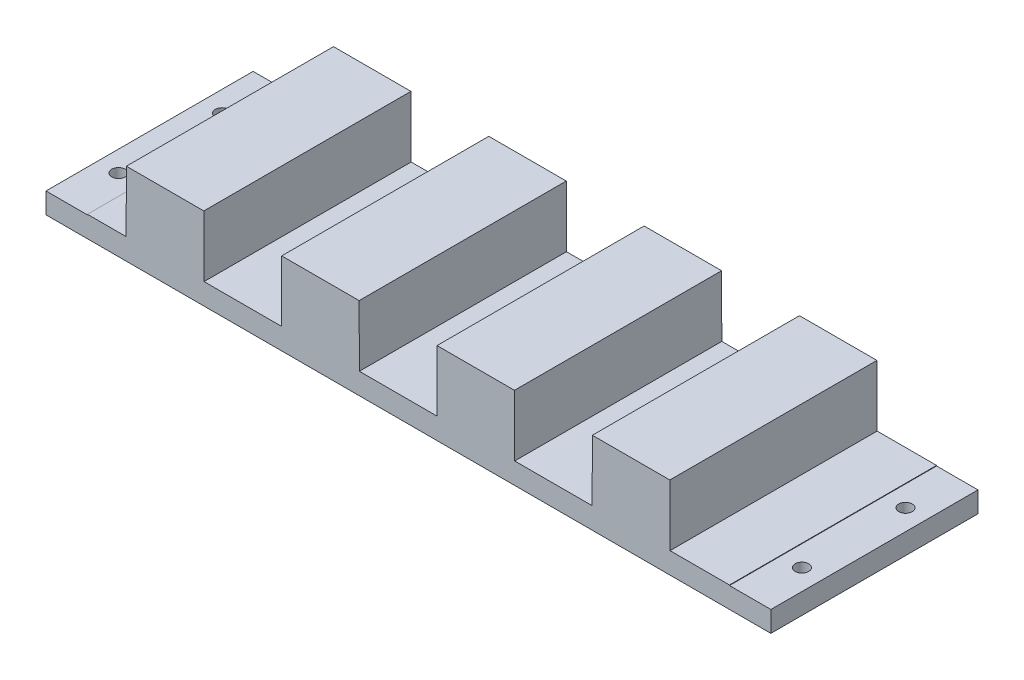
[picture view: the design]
ISO-10303-21;
HEADER;
FILE_DESCRIPTION(('STEP AP214'),'2;1');
FILE_NAME('part.step','',(''),(''),'','','');
FILE_SCHEMA(('AUTOMOTIVE_DESIGN { 1 0 10303 214 1 1 1 1 }'));
ENDSEC;
DATA;
#1=APPLICATION_CONTEXT('core data for automotive mechanical design processes');
#2=APPLICATION_PROTOCOL_DEFINITION('international standard','automotive_design',2000,#1);
#3=PRODUCT_CONTEXT('',#1,'mechanical');
#4=PRODUCT('Part','Part','',(#3));
#5=PRODUCT_RELATED_PRODUCT_CATEGORY('part','',(#4));
#6=PRODUCT_DEFINITION_FORMATION('','',#4);
#7=PRODUCT_DEFINITION_CONTEXT('part definition',#1,'design');
#8=PRODUCT_DEFINITION('design','',#6,#7);
#9=PRODUCT_DEFINITION_SHAPE('','',#8);
#10=(LENGTH_UNIT() NAMED_UNIT(*) SI_UNIT(.MILLI.,.METRE.));
#11=(NAMED_UNIT(*) PLANE_ANGLE_UNIT() SI_UNIT($,.RADIAN.));
#12=(NAMED_UNIT(*) SI_UNIT($,.STERADIAN.) SOLID_ANGLE_UNIT());
#13=UNCERTAINTY_MEASURE_WITH_UNIT(LENGTH_MEASURE(1.E-05),#10,'distance_accuracy_value','');
#14=(GEOMETRIC_REPRESENTATION_CONTEXT(3) GLOBAL_UNCERTAINTY_ASSIGNED_CONTEXT((#13)) GLOBAL_UNIT_ASSIGNED_CONTEXT((#10,
#11,#12)) REPRESENTATION_CONTEXT('',''));
#15=CARTESIAN_POINT('',(0.,0.,0.));
#16=DIRECTION('',(0.,0.,1.));
#17=DIRECTION('',(1.,0.,0.));
#18=AXIS2_PLACEMENT_3D('',#15,#16,#17);
#19=CARTESIAN_POINT('',(0.,0.246057,100.));
#20=DIRECTION('',(1.,0.,0.));
#21=DIRECTION('',(0.,0.,-1.));
#22=AXIS2_PLACEMENT_3D('',#19,#20,#21);
#23=PLANE('',#22);
#24=DIRECTION('',(0.,-1.,0.));
#25=VECTOR('',#24,1.);
#26=CARTESIAN_POINT('',(0.,0.246057,0.));
#27=LINE('',#26,#25);
#28=CARTESIAN_POINT('',(0.,0.246057,0.));
#29=VERTEX_POINT('',#28);
#30=CARTESIAN_POINT('',(0.,0.,0.));
#31=VERTEX_POINT('',#30);
#32=EDGE_CURVE('E229',#29,#31,#27,.T.);
#33=ORIENTED_EDGE('',*,*,#32,.T.);
#34=DIRECTION('',(0.,0.,-1.));
#35=VECTOR('',#34,1.);
#36=CARTESIAN_POINT('',(0.,0.,100.));
#37=LINE('',#36,#35);
#38=CARTESIAN_POINT('',(0.,0.,100.));
#39=VERTEX_POINT('',#38);
#40=EDGE_CURVE('E11',#39,#31,#37,.T.);
#41=ORIENTED_EDGE('',*,*,#40,.F.);
#42=DIRECTION('',(0.,-1.,0.));
#43=VECTOR('',#42,1.);
#44=CARTESIAN_POINT('',(0.,0.246057,100.));
#45=LINE('',#44,#43);
#46=CARTESIAN_POINT('',(0.,0.246057,100.));
#47=VERTEX_POINT('',#46);
#48=EDGE_CURVE('E285',#47,#39,#45,.T.);
#49=ORIENTED_EDGE('',*,*,#48,.F.);
#50=DIRECTION('',(0.,0.,-1.));
#51=VECTOR('',#50,1.);
#52=CARTESIAN_POINT('',(0.,0.246057,100.));
#53=LINE('',#52,#51);
#54=EDGE_CURVE('E225',#47,#29,#53,.T.);
#55=ORIENTED_EDGE('',*,*,#54,.T.);
#56=EDGE_LOOP('',(#33,#41,#49,#55));
#57=FACE_BOUND('',#56,.T.);
#58=ADVANCED_FACE('F35',(#57),#23,.F.);
#59=CARTESIAN_POINT('',(0.,0.,100.));
#60=DIRECTION('',(0.,-1.,0.));
#61=DIRECTION('',(1.,0.,0.));
#62=AXIS2_PLACEMENT_3D('',#59,#60,#61);
#63=PLANE('',#62);
#64=CARTESIAN_POINT('',(-10.,0.,25.));
#65=DIRECTION('',(0.,-1.,0.));
#66=DIRECTION('',(1.,0.,0.));
#67=AXIS2_PLACEMENT_3D('',#64,#65,#66);
#68=CIRCLE('',#67,3.25);
#69=CARTESIAN_POINT('',(-6.75,0.,25.));
#70=VERTEX_POINT('',#69);
#71=EDGE_CURVE('E233',#70,#70,#68,.T.);
#72=ORIENTED_EDGE('',*,*,#71,.T.);
#73=EDGE_LOOP('',(#72));
#74=FACE_BOUND('',#73,.T.);
#75=CARTESIAN_POINT('',(-10.,0.,75.));
#76=DIRECTION('',(0.,-1.,0.));
#77=DIRECTION('',(1.,0.,0.));
#78=AXIS2_PLACEMENT_3D('',#75,#76,#77);
#79=CIRCLE('',#78,3.25);
#80=CARTESIAN_POINT('',(-6.75,0.,75.));
#81=VERTEX_POINT('',#80);
#82=EDGE_CURVE('E354',#81,#81,#79,.T.);
#83=ORIENTED_EDGE('',*,*,#82,.T.);
#84=EDGE_LOOP('',(#83));
#85=FACE_BOUND('',#84,.T.);
#86=DIRECTION('',(-1.,0.,0.));
#87=VECTOR('',#86,1.);
#88=CARTESIAN_POINT('',(0.,0.,0.));
#89=LINE('',#88,#87);
#90=CARTESIAN_POINT('',(-20.,0.,0.));
#91=VERTEX_POINT('',#90);
#92=EDGE_CURVE('E232',#31,#91,#89,.T.);
#93=ORIENTED_EDGE('',*,*,#92,.T.);
#94=DIRECTION('',(0.,0.,-1.));
#95=VECTOR('',#94,1.);
#96=CARTESIAN_POINT('',(-20.,0.,100.));
#97=LINE('',#96,#95);
#98=CARTESIAN_POINT('',(-20.,0.,100.));
#99=VERTEX_POINT('',#98);
#100=EDGE_CURVE('E44',#99,#91,#97,.T.);
#101=ORIENTED_EDGE('',*,*,#100,.F.);
#102=DIRECTION('',(-1.,0.,0.));
#103=VECTOR('',#102,1.);
#104=CARTESIAN_POINT('',(0.,0.,100.));
#105=LINE('',#104,#103);
#106=EDGE_CURVE('E142',#39,#99,#105,.T.);
#107=ORIENTED_EDGE('',*,*,#106,.F.);
#108=ORIENTED_EDGE('',*,*,#40,.T.);
#109=EDGE_LOOP('',(#93,#101,#107,#108));
#110=FACE_BOUND('',#109,.T.);
#111=ADVANCED_FACE('F421',(#74,#85,#110),#63,.F.);
#112=CARTESIAN_POINT('',(-20.,0.,100.));
#113=DIRECTION('',(1.,0.,0.));
#114=DIRECTION('',(0.,0.,-1.));
#115=AXIS2_PLACEMENT_3D('',#112,#113,#114);
#116=PLANE('',#115);
#117=DIRECTION('',(0.,-1.,0.));
#118=VECTOR('',#117,1.);
#119=CARTESIAN_POINT('',(-20.,0.,0.));
#120=LINE('',#119,#118);
#121=CARTESIAN_POINT('',(-20.,-10.,0.));
#122=VERTEX_POINT('',#121);
#123=EDGE_CURVE('E235',#91,#122,#120,.T.);
#124=ORIENTED_EDGE('',*,*,#123,.T.);
#125=DIRECTION('',(0.,0.,-1.));
#126=VECTOR('',#125,1.);
#127=CARTESIAN_POINT('',(-20.,-10.,100.));
#128=LINE('',#127,#126);
#129=CARTESIAN_POINT('',(-20.,-10.,100.));
#130=VERTEX_POINT('',#129);
#131=EDGE_CURVE('E340',#130,#122,#128,.T.);
#132=ORIENTED_EDGE('',*,*,#131,.F.);
#133=DIRECTION('',(0.,-1.,0.));
#134=VECTOR('',#133,1.);
#135=CARTESIAN_POINT('',(-20.,0.,100.));
#136=LINE('',#135,#134);
#137=EDGE_CURVE('E369',#99,#130,#136,.T.);
#138=ORIENTED_EDGE('',*,*,#137,.F.);
#139=ORIENTED_EDGE('',*,*,#100,.T.);
#140=EDGE_LOOP('',(#124,#132,#138,#139));
#141=FACE_BOUND('',#140,.T.);
#142=ADVANCED_FACE('F424',(#141),#116,.F.);
#143=CARTESIAN_POINT('',(-20.,-10.,100.));
#144=DIRECTION('',(0.,1.,0.));
#145=DIRECTION('',(-1.,0.,0.));
#146=AXIS2_PLACEMENT_3D('',#143,#144,#145);
#147=PLANE('',#146);
#148=CARTESIAN_POINT('',(-10.,-10.,25.));
#149=DIRECTION('',(0.,1.,0.));
#150=DIRECTION('',(-1.,0.,0.));
#151=AXIS2_PLACEMENT_3D('',#148,#149,#150);
#152=CIRCLE('',#151,3.25);
#153=CARTESIAN_POINT('',(-6.75,-9.99999999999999,25.));
#154=VERTEX_POINT('',#153);
#155=EDGE_CURVE('E38',#154,#154,#152,.T.);
#156=ORIENTED_EDGE('',*,*,#155,.T.);
#157=EDGE_LOOP('',(#156));
#158=FACE_BOUND('',#157,.T.);
#159=CARTESIAN_POINT('',(320.,-10.,25.));
#160=DIRECTION('',(0.,1.,0.));
#161=DIRECTION('',(-1.,0.,0.));
#162=AXIS2_PLACEMENT_3D('',#159,#160,#161);
#163=CIRCLE('',#162,3.25000000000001);
#164=CARTESIAN_POINT('',(323.25,-9.99999999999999,25.));
#165=VERTEX_POINT('',#164);
#166=EDGE_CURVE('E351',#165,#165,#163,.T.);
#167=ORIENTED_EDGE('',*,*,#166,.T.);
#168=EDGE_LOOP('',(#167));
#169=FACE_BOUND('',#168,.T.);
#170=CARTESIAN_POINT('',(320.,-10.,75.));
#171=DIRECTION('',(0.,1.,0.));
#172=DIRECTION('',(-1.,0.,0.));
#173=AXIS2_PLACEMENT_3D('',#170,#171,#172);
#174=CIRCLE('',#173,3.25000000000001);
#175=CARTESIAN_POINT('',(323.25,-9.99999999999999,75.));
#176=VERTEX_POINT('',#175);
#177=EDGE_CURVE('E348',#176,#176,#174,.T.);
#178=ORIENTED_EDGE('',*,*,#177,.T.);
#179=EDGE_LOOP('',(#178));
#180=FACE_BOUND('',#179,.T.);
#181=CARTESIAN_POINT('',(-10.,-10.,75.));
#182=DIRECTION('',(0.,1.,0.));
#183=DIRECTION('',(-1.,0.,0.));
#184=AXIS2_PLACEMENT_3D('',#181,#182,#183);
#185=CIRCLE('',#184,3.25);
#186=CARTESIAN_POINT('',(-6.75,-9.99999999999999,75.));
#187=VERTEX_POINT('',#186);
#188=EDGE_CURVE('E352',#187,#187,#185,.T.);
#189=ORIENTED_EDGE('',*,*,#188,.T.);
#190=EDGE_LOOP('',(#189));
#191=FACE_BOUND('',#190,.T.);
#192=DIRECTION('',(1.,0.,0.));
#193=VECTOR('',#192,1.);
#194=CARTESIAN_POINT('',(-20.,-10.,0.));
#195=LINE('',#194,#193);
#196=CARTESIAN_POINT('',(330.,-10.,0.));
#197=VERTEX_POINT('',#196);
#198=EDGE_CURVE('E237',#122,#197,#195,.T.);
#199=ORIENTED_EDGE('',*,*,#198,.T.);
#200=DIRECTION('',(0.,0.,-1.));
#201=VECTOR('',#200,1.);
#202=CARTESIAN_POINT('',(330.,-10.,100.));
#203=LINE('',#202,#201);
#204=CARTESIAN_POINT('',(330.,-10.,100.));
#205=VERTEX_POINT('',#204);
#206=EDGE_CURVE('E337',#205,#197,#203,.T.);
#207=ORIENTED_EDGE('',*,*,#206,.F.);
#208=DIRECTION('',(1.,0.,0.));
#209=VECTOR('',#208,1.);
#210=CARTESIAN_POINT('',(-20.,-10.,100.));
#211=LINE('',#210,#209);
#212=EDGE_CURVE('E371',#130,#205,#211,.T.);
#213=ORIENTED_EDGE('',*,*,#212,.F.);
#214=ORIENTED_EDGE('',*,*,#131,.T.);
#215=EDGE_LOOP('',(#199,#207,#213,#214));
#216=FACE_BOUND('',#215,.T.);
#217=ADVANCED_FACE('F429',(#158,#169,#180,#191,#216),#147,.F.);
#218=CARTESIAN_POINT('',(330.,-10.,100.));
#219=DIRECTION('',(-1.,0.,0.));
#220=DIRECTION('',(0.,0.,1.));
#221=AXIS2_PLACEMENT_3D('',#218,#219,#220);
#222=PLANE('',#221);
#223=DIRECTION('',(0.,1.,0.));
#224=VECTOR('',#223,1.);
#225=CARTESIAN_POINT('',(330.,-10.,0.));
#226=LINE('',#225,#224);
#227=CARTESIAN_POINT('',(330.,0.,0.));
#228=VERTEX_POINT('',#227);
#229=EDGE_CURVE('E239',#197,#228,#226,.T.);
#230=ORIENTED_EDGE('',*,*,#229,.T.);
#231=DIRECTION('',(0.,0.,-1.));
#232=VECTOR('',#231,1.);
#233=CARTESIAN_POINT('',(330.,0.,100.));
#234=LINE('',#233,#232);
#235=CARTESIAN_POINT('',(330.,0.,100.));
#236=VERTEX_POINT('',#235);
#237=EDGE_CURVE('E334',#236,#228,#234,.T.);
#238=ORIENTED_EDGE('',*,*,#237,.F.);
#239=DIRECTION('',(0.,1.,0.));
#240=VECTOR('',#239,1.);
#241=CARTESIAN_POINT('',(330.,-10.,100.));
#242=LINE('',#241,#240);
#243=EDGE_CURVE('E373',#205,#236,#242,.T.);
#244=ORIENTED_EDGE('',*,*,#243,.F.);
#245=ORIENTED_EDGE('',*,*,#206,.T.);
#246=EDGE_LOOP('',(#230,#238,#244,#245));
#247=FACE_BOUND('',#246,.T.);
#248=ADVANCED_FACE('F435',(#247),#222,.F.);
#249=CARTESIAN_POINT('',(330.,0.,100.));
#250=DIRECTION('',(0.,-1.,0.));
#251=DIRECTION('',(1.,0.,0.));
#252=AXIS2_PLACEMENT_3D('',#249,#250,#251);
#253=PLANE('',#252);
#254=CARTESIAN_POINT('',(320.,0.,25.));
#255=DIRECTION('',(0.,-1.,0.));
#256=DIRECTION('',(1.,0.,0.));
#257=AXIS2_PLACEMENT_3D('',#254,#255,#256);
#258=CIRCLE('',#257,3.25000000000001);
#259=CARTESIAN_POINT('',(323.25,0.,25.));
#260=VERTEX_POINT('',#259);
#261=EDGE_CURVE('E349',#260,#260,#258,.T.);
#262=ORIENTED_EDGE('',*,*,#261,.T.);
#263=EDGE_LOOP('',(#262));
#264=FACE_BOUND('',#263,.T.);
#265=CARTESIAN_POINT('',(320.,0.,75.));
#266=DIRECTION('',(0.,-1.,0.));
#267=DIRECTION('',(1.,0.,0.));
#268=AXIS2_PLACEMENT_3D('',#265,#266,#267);
#269=CIRCLE('',#268,3.25000000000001);
#270=CARTESIAN_POINT('',(323.25,0.,75.));
#271=VERTEX_POINT('',#270);
#272=EDGE_CURVE('E345',#271,#271,#269,.T.);
#273=ORIENTED_EDGE('',*,*,#272,.T.);
#274=EDGE_LOOP('',(#273));
#275=FACE_BOUND('',#274,.T.);
#276=DIRECTION('',(-1.,0.,0.));
#277=VECTOR('',#276,1.);
#278=CARTESIAN_POINT('',(330.,0.,0.));
#279=LINE('',#278,#277);
#280=CARTESIAN_POINT('',(310.000009,0.,0.));
#281=VERTEX_POINT('',#280);
#282=EDGE_CURVE('E241',#228,#281,#279,.T.);
#283=ORIENTED_EDGE('',*,*,#282,.T.);
#284=DIRECTION('',(0.,0.,-1.));
#285=VECTOR('',#284,1.);
#286=CARTESIAN_POINT('',(310.000009,0.,100.));
#287=LINE('',#286,#285);
#288=CARTESIAN_POINT('',(310.000009,0.,100.));
#289=VERTEX_POINT('',#288);
#290=EDGE_CURVE('E331',#289,#281,#287,.T.);
#291=ORIENTED_EDGE('',*,*,#290,.F.);
#292=DIRECTION('',(-1.,0.,0.));
#293=VECTOR('',#292,1.);
#294=CARTESIAN_POINT('',(330.,0.,100.));
#295=LINE('',#294,#293);
#296=EDGE_CURVE('E375',#236,#289,#295,.T.);
#297=ORIENTED_EDGE('',*,*,#296,.F.);
#298=ORIENTED_EDGE('',*,*,#237,.T.);
#299=EDGE_LOOP('',(#283,#291,#297,#298));
#300=FACE_BOUND('',#299,.T.);
#301=ADVANCED_FACE('F439',(#264,#275,#300),#253,.F.);
#302=CARTESIAN_POINT('',(310.000009,0.,100.));
#303=DIRECTION('',(-1.,0.,0.));
#304=DIRECTION('',(0.,0.,1.));
#305=AXIS2_PLACEMENT_3D('',#302,#303,#304);
#306=PLANE('',#305);
#307=DIRECTION('',(0.,1.,0.));
#308=VECTOR('',#307,1.);
#309=CARTESIAN_POINT('',(310.000009,0.,0.));
#310=LINE('',#309,#308);
#311=CARTESIAN_POINT('',(310.000009,0.246057,0.));
#312=VERTEX_POINT('',#311);
#313=EDGE_CURVE('E243',#281,#312,#310,.T.);
#314=ORIENTED_EDGE('',*,*,#313,.T.);
#315=DIRECTION('',(0.,0.,-1.));
#316=VECTOR('',#315,1.);
#317=CARTESIAN_POINT('',(310.000009,0.246057,100.));
#318=LINE('',#317,#316);
#319=CARTESIAN_POINT('',(310.000009,0.246057,100.));
#320=VERTEX_POINT('',#319);
#321=EDGE_CURVE('E328',#320,#312,#318,.T.);
#322=ORIENTED_EDGE('',*,*,#321,.F.);
#323=DIRECTION('',(0.,1.,0.));
#324=VECTOR('',#323,1.);
#325=CARTESIAN_POINT('',(310.000009,0.,100.));
#326=LINE('',#325,#324);
#327=EDGE_CURVE('E377',#289,#320,#326,.T.);
#328=ORIENTED_EDGE('',*,*,#327,.F.);
#329=ORIENTED_EDGE('',*,*,#290,.T.);
#330=EDGE_LOOP('',(#314,#322,#328,#329));
#331=FACE_BOUND('',#330,.T.);
#332=ADVANCED_FACE('F444',(#331),#306,.F.);
#333=CARTESIAN_POINT('',(281.300013,0.246057,100.));
#334=DIRECTION('',(0.,-1.,0.));
#335=DIRECTION('',(0.,0.,-1.));
#336=AXIS2_PLACEMENT_3D('',#333,#334,#335);
#337=PLANE('',#336);
#338=DIRECTION('',(-1.,0.,0.));
#339=VECTOR('',#338,1.);
#340=CARTESIAN_POINT('',(281.300013,0.246057,0.));
#341=LINE('',#340,#339);
#342=CARTESIAN_POINT('',(281.300013,0.246057,0.));
#343=VERTEX_POINT('',#342);
#344=EDGE_CURVE('E246',#312,#343,#341,.T.);
#345=ORIENTED_EDGE('',*,*,#344,.T.);
#346=DIRECTION('',(0.,0.,-1.));
#347=VECTOR('',#346,1.);
#348=CARTESIAN_POINT('',(281.300013,0.246057,100.));
#349=LINE('',#348,#347);
#350=CARTESIAN_POINT('',(281.300013,0.246057,100.));
#351=VERTEX_POINT('',#350);
#352=EDGE_CURVE('E325',#351,#343,#349,.T.);
#353=ORIENTED_EDGE('',*,*,#352,.F.);
#354=DIRECTION('',(-1.,0.,0.));
#355=VECTOR('',#354,1.);
#356=CARTESIAN_POINT('',(309.899991,0.246057,100.));
#357=LINE('',#356,#355);
#358=EDGE_CURVE('E379',#320,#351,#357,.T.);
#359=ORIENTED_EDGE('',*,*,#358,.F.);
#360=ORIENTED_EDGE('',*,*,#321,.T.);
#361=EDGE_LOOP('',(#345,#353,#359,#360));
#362=FACE_BOUND('',#361,.T.);
#363=ADVANCED_FACE('F450',(#362),#337,.F.);
#364=CARTESIAN_POINT('',(281.200032,29.749822,100.));
#365=DIRECTION('',(-0.999994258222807,-0.00338873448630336,0.));
#366=DIRECTION('',(0.00338873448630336,-0.999994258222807,0.));
#367=AXIS2_PLACEMENT_3D('',#364,#365,#366);
#368=PLANE('',#367);
#369=DIRECTION('',(-0.00338873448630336,0.999994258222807,0.));
#370=VECTOR('',#369,1.);
#371=CARTESIAN_POINT('',(281.200032,29.749822,0.));
#372=LINE('',#371,#370);
#373=CARTESIAN_POINT('',(281.200032,29.749822,0.));
#374=VERTEX_POINT('',#373);
#375=EDGE_CURVE('E248',#343,#374,#372,.T.);
#376=ORIENTED_EDGE('',*,*,#375,.T.);
#377=DIRECTION('',(0.,0.,-1.));
#378=VECTOR('',#377,1.);
#379=CARTESIAN_POINT('',(281.200032,29.749822,100.));
#380=LINE('',#379,#378);
#381=CARTESIAN_POINT('',(281.200032,29.749822,100.));
#382=VERTEX_POINT('',#381);
#383=EDGE_CURVE('E322',#382,#374,#380,.T.);
#384=ORIENTED_EDGE('',*,*,#383,.F.);
#385=DIRECTION('',(-0.00338873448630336,0.999994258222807,0.));
#386=VECTOR('',#385,1.);
#387=CARTESIAN_POINT('',(281.200032,29.749822,100.));
#388=LINE('',#387,#386);
#389=EDGE_CURVE('E381',#351,#382,#388,.T.);
#390=ORIENTED_EDGE('',*,*,#389,.F.);
#391=ORIENTED_EDGE('',*,*,#352,.T.);
#392=EDGE_LOOP('',(#376,#384,#390,#391));
#393=FACE_BOUND('',#392,.T.);
#394=ADVANCED_FACE('F453',(#393),#368,.F.);
#395=CARTESIAN_POINT('',(243.800032,29.749822,100.));
#396=DIRECTION('',(0.,-1.,0.));
#397=DIRECTION('',(0.,0.,-1.));
#398=AXIS2_PLACEMENT_3D('',#395,#396,#397);
#399=PLANE('',#398);
#400=DIRECTION('',(-1.,0.,0.));
#401=VECTOR('',#400,1.);
#402=CARTESIAN_POINT('',(243.800032,29.749822,0.));
#403=LINE('',#402,#401);
#404=CARTESIAN_POINT('',(243.800032,29.749822,0.));
#405=VERTEX_POINT('',#404);
#406=EDGE_CURVE('E251',#374,#405,#403,.T.);
#407=ORIENTED_EDGE('',*,*,#406,.T.);
#408=DIRECTION('',(0.,0.,-1.));
#409=VECTOR('',#408,1.);
#410=CARTESIAN_POINT('',(243.800032,29.749822,100.));
#411=LINE('',#410,#409);
#412=CARTESIAN_POINT('',(243.800032,29.749822,100.));
#413=VERTEX_POINT('',#412);
#414=EDGE_CURVE('E319',#413,#405,#411,.T.);
#415=ORIENTED_EDGE('',*,*,#414,.F.);
#416=DIRECTION('',(-1.,0.,0.));
#417=VECTOR('',#416,1.);
#418=CARTESIAN_POINT('',(281.100014,29.749822,100.));
#419=LINE('',#418,#417);
#420=EDGE_CURVE('E383',#382,#413,#419,.T.);
#421=ORIENTED_EDGE('',*,*,#420,.F.);
#422=ORIENTED_EDGE('',*,*,#383,.T.);
#423=EDGE_LOOP('',(#407,#415,#421,#422));
#424=FACE_BOUND('',#423,.T.);
#425=ADVANCED_FACE('F457',(#424),#399,.F.);
#426=CARTESIAN_POINT('',(243.700014,0.246057,100.));
#427=DIRECTION('',(0.999994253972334,-0.00338998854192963,0.));
#428=DIRECTION('',(0.00338998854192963,0.999994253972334,0.));
#429=AXIS2_PLACEMENT_3D('',#426,#427,#428);
#430=PLANE('',#429);
#431=DIRECTION('',(-0.00338998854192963,-0.999994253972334,0.));
#432=VECTOR('',#431,1.);
#433=CARTESIAN_POINT('',(243.700014,0.246057,0.));
#434=LINE('',#433,#432);
#435=CARTESIAN_POINT('',(243.700014,0.246057,0.));
#436=VERTEX_POINT('',#435);
#437=EDGE_CURVE('E253',#405,#436,#434,.T.);
#438=ORIENTED_EDGE('',*,*,#437,.T.);
#439=DIRECTION('',(0.,0.,-1.));
#440=VECTOR('',#439,1.);
#441=CARTESIAN_POINT('',(243.700014,0.246057,100.));
#442=LINE('',#441,#440);
#443=CARTESIAN_POINT('',(243.700014,0.246057,100.));
#444=VERTEX_POINT('',#443);
#445=EDGE_CURVE('E316',#444,#436,#442,.T.);
#446=ORIENTED_EDGE('',*,*,#445,.F.);
#447=DIRECTION('',(-0.00338998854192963,-0.999994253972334,0.));
#448=VECTOR('',#447,1.);
#449=CARTESIAN_POINT('',(243.700014,0.246057,100.));
#450=LINE('',#449,#448);
#451=EDGE_CURVE('E385',#413,#444,#450,.T.);
#452=ORIENTED_EDGE('',*,*,#451,.F.);
#453=ORIENTED_EDGE('',*,*,#414,.T.);
#454=EDGE_LOOP('',(#438,#446,#452,#453));
#455=FACE_BOUND('',#454,.T.);
#456=ADVANCED_FACE('F463',(#455),#430,.F.);
#457=CARTESIAN_POINT('',(206.300014,0.246057,100.));
#458=DIRECTION('',(0.,-1.,0.));
#459=DIRECTION('',(0.,0.,-1.));
#460=AXIS2_PLACEMENT_3D('',#457,#458,#459);
#461=PLANE('',#460);
#462=DIRECTION('',(-1.,0.,0.));
#463=VECTOR('',#462,1.);
#464=CARTESIAN_POINT('',(206.300014,0.246057,0.));
#465=LINE('',#464,#463);
#466=CARTESIAN_POINT('',(206.300014,0.246057,0.));
#467=VERTEX_POINT('',#466);
#468=EDGE_CURVE('E256',#436,#467,#465,.T.);
#469=ORIENTED_EDGE('',*,*,#468,.T.);
#470=DIRECTION('',(0.,0.,-1.));
#471=VECTOR('',#470,1.);
#472=CARTESIAN_POINT('',(206.300014,0.246057,100.));
#473=LINE('',#472,#471);
#474=CARTESIAN_POINT('',(206.300014,0.246057,100.));
#475=VERTEX_POINT('',#474);
#476=EDGE_CURVE('E313',#475,#467,#473,.T.);
#477=ORIENTED_EDGE('',*,*,#476,.F.);
#478=DIRECTION('',(-1.,0.,0.));
#479=VECTOR('',#478,1.);
#480=CARTESIAN_POINT('',(243.600034,0.246057,100.));
#481=LINE('',#480,#479);
#482=EDGE_CURVE('E387',#444,#475,#481,.T.);
#483=ORIENTED_EDGE('',*,*,#482,.F.);
#484=ORIENTED_EDGE('',*,*,#445,.T.);
#485=EDGE_LOOP('',(#469,#477,#483,#484));
#486=FACE_BOUND('',#485,.T.);
#487=ADVANCED_FACE('F466',(#486),#461,.F.);
#488=CARTESIAN_POINT('',(206.199996,29.749822,100.));
#489=DIRECTION('',(-0.999994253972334,-0.00338998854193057,0.));
#490=DIRECTION('',(0.00338998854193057,-0.999994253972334,0.));
#491=AXIS2_PLACEMENT_3D('',#488,#489,#490);
#492=PLANE('',#491);
#493=DIRECTION('',(-0.00338998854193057,0.999994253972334,0.));
#494=VECTOR('',#493,1.);
#495=CARTESIAN_POINT('',(206.199996,29.749822,0.));
#496=LINE('',#495,#494);
#497=CARTESIAN_POINT('',(206.199996,29.749822,0.));
#498=VERTEX_POINT('',#497);
#499=EDGE_CURVE('E258',#467,#498,#496,.T.);
#500=ORIENTED_EDGE('',*,*,#499,.T.);
#501=DIRECTION('',(0.,0.,-1.));
#502=VECTOR('',#501,1.);
#503=CARTESIAN_POINT('',(206.199996,29.749822,100.));
#504=LINE('',#503,#502);
#505=CARTESIAN_POINT('',(206.199996,29.749822,100.));
#506=VERTEX_POINT('',#505);
#507=EDGE_CURVE('E310',#506,#498,#504,.T.);
#508=ORIENTED_EDGE('',*,*,#507,.F.);
#509=DIRECTION('',(-0.00338998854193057,0.999994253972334,0.));
#510=VECTOR('',#509,1.);
#511=CARTESIAN_POINT('',(206.199996,29.749822,100.));
#512=LINE('',#511,#510);
#513=EDGE_CURVE('E389',#475,#506,#512,.T.);
#514=ORIENTED_EDGE('',*,*,#513,.F.);
#515=ORIENTED_EDGE('',*,*,#476,.T.);
#516=EDGE_LOOP('',(#500,#508,#514,#515));
#517=FACE_BOUND('',#516,.T.);
#518=ADVANCED_FACE('F471',(#517),#492,.F.);
#519=CARTESIAN_POINT('',(168.799996,29.749822,100.));
#520=DIRECTION('',(0.,-1.,0.));
#521=DIRECTION('',(0.,0.,-1.));
#522=AXIS2_PLACEMENT_3D('',#519,#520,#521);
#523=PLANE('',#522);
#524=DIRECTION('',(-1.,0.,0.));
#525=VECTOR('',#524,1.);
#526=CARTESIAN_POINT('',(168.799996,29.749822,0.));
#527=LINE('',#526,#525);
#528=CARTESIAN_POINT('',(168.799996,29.749822,0.));
#529=VERTEX_POINT('',#528);
#530=EDGE_CURVE('E261',#498,#529,#527,.T.);
#531=ORIENTED_EDGE('',*,*,#530,.T.);
#532=DIRECTION('',(0.,0.,-1.));
#533=VECTOR('',#532,1.);
#534=CARTESIAN_POINT('',(168.799996,29.749822,100.));
#535=LINE('',#534,#533);
#536=CARTESIAN_POINT('',(168.799996,29.749822,100.));
#537=VERTEX_POINT('',#536);
#538=EDGE_CURVE('E307',#537,#529,#535,.T.);
#539=ORIENTED_EDGE('',*,*,#538,.F.);
#540=DIRECTION('',(-1.,0.,0.));
#541=VECTOR('',#540,1.);
#542=CARTESIAN_POINT('',(206.100016,29.749822,100.));
#543=LINE('',#542,#541);
#544=EDGE_CURVE('E391',#506,#537,#543,.T.);
#545=ORIENTED_EDGE('',*,*,#544,.F.);
#546=ORIENTED_EDGE('',*,*,#507,.T.);
#547=EDGE_LOOP('',(#531,#539,#545,#546));
#548=FACE_BOUND('',#547,.T.);
#549=ADVANCED_FACE('F477',(#548),#523,.F.);
#550=CARTESIAN_POINT('',(168.699978,0.246057,100.));
#551=DIRECTION('',(0.999994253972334,-0.00338998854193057,0.));
#552=DIRECTION('',(0.00338998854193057,0.999994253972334,0.));
#553=AXIS2_PLACEMENT_3D('',#550,#551,#552);
#554=PLANE('',#553);
#555=DIRECTION('',(-0.00338998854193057,-0.999994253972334,0.));
#556=VECTOR('',#555,1.);
#557=CARTESIAN_POINT('',(168.699978,0.246057,0.));
#558=LINE('',#557,#556);
#559=CARTESIAN_POINT('',(168.699978,0.246057,0.));
#560=VERTEX_POINT('',#559);
#561=EDGE_CURVE('E263',#529,#560,#558,.T.);
#562=ORIENTED_EDGE('',*,*,#561,.T.);
#563=DIRECTION('',(0.,0.,-1.));
#564=VECTOR('',#563,1.);
#565=CARTESIAN_POINT('',(168.699978,0.246057,100.));
#566=LINE('',#565,#564);
#567=CARTESIAN_POINT('',(168.699978,0.246057,100.));
#568=VERTEX_POINT('',#567);
#569=EDGE_CURVE('E304',#568,#560,#566,.T.);
#570=ORIENTED_EDGE('',*,*,#569,.F.);
#571=DIRECTION('',(-0.00338998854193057,-0.999994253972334,0.));
#572=VECTOR('',#571,1.);
#573=CARTESIAN_POINT('',(168.699978,0.246057,100.));
#574=LINE('',#573,#572);
#575=EDGE_CURVE('E393',#537,#568,#574,.T.);
#576=ORIENTED_EDGE('',*,*,#575,.F.);
#577=ORIENTED_EDGE('',*,*,#538,.T.);
#578=EDGE_LOOP('',(#562,#570,#576,#577));
#579=FACE_BOUND('',#578,.T.);
#580=ADVANCED_FACE('F480',(#579),#554,.F.);
#581=CARTESIAN_POINT('',(131.300016,0.246057,100.));
#582=DIRECTION('',(0.,-1.,0.));
#583=DIRECTION('',(0.,0.,-1.));
#584=AXIS2_PLACEMENT_3D('',#581,#582,#583);
#585=PLANE('',#584);
#586=DIRECTION('',(-1.,0.,0.));
#587=VECTOR('',#586,1.);
#588=CARTESIAN_POINT('',(131.300016,0.246057,0.));
#589=LINE('',#588,#587);
#590=CARTESIAN_POINT('',(131.300016,0.246057,0.));
#591=VERTEX_POINT('',#590);
#592=EDGE_CURVE('E266',#560,#591,#589,.T.);
#593=ORIENTED_EDGE('',*,*,#592,.T.);
#594=DIRECTION('',(0.,0.,-1.));
#595=VECTOR('',#594,1.);
#596=CARTESIAN_POINT('',(131.300016,0.246057,100.));
#597=LINE('',#596,#595);
#598=CARTESIAN_POINT('',(131.300016,0.246057,100.));
#599=VERTEX_POINT('',#598);
#600=EDGE_CURVE('E301',#599,#591,#597,.T.);
#601=ORIENTED_EDGE('',*,*,#600,.F.);
#602=DIRECTION('',(-1.,0.,0.));
#603=VECTOR('',#602,1.);
#604=CARTESIAN_POINT('',(168.599998,0.246057,100.));
#605=LINE('',#604,#603);
#606=EDGE_CURVE('E395',#568,#599,#605,.T.);
#607=ORIENTED_EDGE('',*,*,#606,.F.);
#608=ORIENTED_EDGE('',*,*,#569,.T.);
#609=EDGE_LOOP('',(#593,#601,#607,#608));
#610=FACE_BOUND('',#609,.T.);
#611=ADVANCED_FACE('F484',(#610),#585,.F.);
#612=CARTESIAN_POINT('',(131.199998,29.749822,100.));
#613=DIRECTION('',(-0.999994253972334,-0.00338998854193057,0.));
#614=DIRECTION('',(0.00338998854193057,-0.999994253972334,0.));
#615=AXIS2_PLACEMENT_3D('',#612,#613,#614);
#616=PLANE('',#615);
#617=DIRECTION('',(-0.00338998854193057,0.999994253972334,0.));
#618=VECTOR('',#617,1.);
#619=CARTESIAN_POINT('',(131.199998,29.749822,0.));
#620=LINE('',#619,#618);
#621=CARTESIAN_POINT('',(131.199998,29.749822,0.));
#622=VERTEX_POINT('',#621);
#623=EDGE_CURVE('E268',#591,#622,#620,.T.);
#624=ORIENTED_EDGE('',*,*,#623,.T.);
#625=DIRECTION('',(0.,0.,-1.));
#626=VECTOR('',#625,1.);
#627=CARTESIAN_POINT('',(131.199998,29.749822,100.));
#628=LINE('',#627,#626);
#629=CARTESIAN_POINT('',(131.199998,29.749822,100.));
#630=VERTEX_POINT('',#629);
#631=EDGE_CURVE('E298',#630,#622,#628,.T.);
#632=ORIENTED_EDGE('',*,*,#631,.F.);
#633=DIRECTION('',(-0.00338998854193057,0.999994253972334,0.));
#634=VECTOR('',#633,1.);
#635=CARTESIAN_POINT('',(131.199998,29.749822,100.));
#636=LINE('',#635,#634);
#637=EDGE_CURVE('E397',#599,#630,#636,.T.);
#638=ORIENTED_EDGE('',*,*,#637,.F.);
#639=ORIENTED_EDGE('',*,*,#600,.T.);
#640=EDGE_LOOP('',(#624,#632,#638,#639));
#641=FACE_BOUND('',#640,.T.);
#642=ADVANCED_FACE('F490',(#641),#616,.F.);
#643=CARTESIAN_POINT('',(93.799998,29.749822,100.));
#644=DIRECTION('',(0.,-1.,0.));
#645=DIRECTION('',(0.,0.,-1.));
#646=AXIS2_PLACEMENT_3D('',#643,#644,#645);
#647=PLANE('',#646);
#648=DIRECTION('',(-1.,0.,0.));
#649=VECTOR('',#648,1.);
#650=CARTESIAN_POINT('',(93.799998,29.749822,0.));
#651=LINE('',#650,#649);
#652=CARTESIAN_POINT('',(93.799998,29.749822,0.));
#653=VERTEX_POINT('',#652);
#654=EDGE_CURVE('E271',#622,#653,#651,.T.);
#655=ORIENTED_EDGE('',*,*,#654,.T.);
#656=DIRECTION('',(0.,0.,-1.));
#657=VECTOR('',#656,1.);
#658=CARTESIAN_POINT('',(93.799998,29.749822,100.));
#659=LINE('',#658,#657);
#660=CARTESIAN_POINT('',(93.799998,29.749822,100.));
#661=VERTEX_POINT('',#660);
#662=EDGE_CURVE('E295',#661,#653,#659,.T.);
#663=ORIENTED_EDGE('',*,*,#662,.F.);
#664=DIRECTION('',(-1.,0.,0.));
#665=VECTOR('',#664,1.);
#666=CARTESIAN_POINT('',(131.100017,29.749822,100.));
#667=LINE('',#666,#665);
#668=EDGE_CURVE('E399',#630,#661,#667,.T.);
#669=ORIENTED_EDGE('',*,*,#668,.F.);
#670=ORIENTED_EDGE('',*,*,#631,.T.);
#671=EDGE_LOOP('',(#655,#663,#669,#670));
#672=FACE_BOUND('',#671,.T.);
#673=ADVANCED_FACE('F493',(#672),#647,.F.);
#674=CARTESIAN_POINT('',(93.700017,0.246057,100.));
#675=DIRECTION('',(0.999994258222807,-0.00338873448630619,0.));
#676=DIRECTION('',(0.00338873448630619,0.999994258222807,0.));
#677=AXIS2_PLACEMENT_3D('',#674,#675,#676);
#678=PLANE('',#677);
#679=DIRECTION('',(-0.00338873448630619,-0.999994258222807,0.));
#680=VECTOR('',#679,1.);
#681=CARTESIAN_POINT('',(93.700017,0.246057,0.));
#682=LINE('',#681,#680);
#683=CARTESIAN_POINT('',(93.700017,0.246057,0.));
#684=VERTEX_POINT('',#683);
#685=EDGE_CURVE('E273',#653,#684,#682,.T.);
#686=ORIENTED_EDGE('',*,*,#685,.T.);
#687=DIRECTION('',(0.,0.,-1.));
#688=VECTOR('',#687,1.);
#689=CARTESIAN_POINT('',(93.700017,0.246057,100.));
#690=LINE('',#689,#688);
#691=CARTESIAN_POINT('',(93.700017,0.246057,100.));
#692=VERTEX_POINT('',#691);
#693=EDGE_CURVE('E292',#692,#684,#690,.T.);
#694=ORIENTED_EDGE('',*,*,#693,.F.);
#695=DIRECTION('',(-0.00338873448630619,-0.999994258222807,0.));
#696=VECTOR('',#695,1.);
#697=CARTESIAN_POINT('',(93.700017,0.246057,100.));
#698=LINE('',#697,#696);
#699=EDGE_CURVE('E401',#661,#692,#698,.T.);
#700=ORIENTED_EDGE('',*,*,#699,.F.);
#701=ORIENTED_EDGE('',*,*,#662,.T.);
#702=EDGE_LOOP('',(#686,#694,#700,#701));
#703=FACE_BOUND('',#702,.T.);
#704=ADVANCED_FACE('F495',(#703),#678,.F.);
#705=CARTESIAN_POINT('',(56.300017,0.246057,100.));
#706=DIRECTION('',(0.,-1.,0.));
#707=DIRECTION('',(0.,0.,-1.));
#708=AXIS2_PLACEMENT_3D('',#705,#706,#707);
#709=PLANE('',#708);
#710=DIRECTION('',(-1.,0.,0.));
#711=VECTOR('',#710,1.);
#712=CARTESIAN_POINT('',(56.300017,0.246057,0.));
#713=LINE('',#712,#711);
#714=CARTESIAN_POINT('',(56.300017,0.246057,0.));
#715=VERTEX_POINT('',#714);
#716=EDGE_CURVE('E276',#684,#715,#713,.T.);
#717=ORIENTED_EDGE('',*,*,#716,.T.);
#718=DIRECTION('',(0.,0.,-1.));
#719=VECTOR('',#718,1.);
#720=CARTESIAN_POINT('',(56.300017,0.246057,100.));
#721=LINE('',#720,#719);
#722=CARTESIAN_POINT('',(56.300017,0.246057,100.));
#723=VERTEX_POINT('',#722);
#724=EDGE_CURVE('E289',#723,#715,#721,.T.);
#725=ORIENTED_EDGE('',*,*,#724,.F.);
#726=DIRECTION('',(-1.,0.,0.));
#727=VECTOR('',#726,1.);
#728=CARTESIAN_POINT('',(93.599999,0.246057,100.));
#729=LINE('',#728,#727);
#730=EDGE_CURVE('E403',#692,#723,#729,.T.);
#731=ORIENTED_EDGE('',*,*,#730,.F.);
#732=ORIENTED_EDGE('',*,*,#693,.T.);
#733=EDGE_LOOP('',(#717,#725,#731,#732));
#734=FACE_BOUND('',#733,.T.);
#735=ADVANCED_FACE('F409',(#734),#709,.F.);
#736=CARTESIAN_POINT('',(56.199999,29.749822,100.));
#737=DIRECTION('',(-0.999994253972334,-0.00338998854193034,0.));
#738=DIRECTION('',(0.00338998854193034,-0.999994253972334,0.));
#739=AXIS2_PLACEMENT_3D('',#736,#737,#738);
#740=PLANE('',#739);
#741=DIRECTION('',(-0.00338998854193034,0.999994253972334,0.));
#742=VECTOR('',#741,1.);
#743=CARTESIAN_POINT('',(56.199999,29.749822,0.));
#744=LINE('',#743,#742);
#745=CARTESIAN_POINT('',(56.199999,29.749822,0.));
#746=VERTEX_POINT('',#745);
#747=EDGE_CURVE('E278',#715,#746,#744,.T.);
#748=ORIENTED_EDGE('',*,*,#747,.T.);
#749=DIRECTION('',(0.,0.,-1.));
#750=VECTOR('',#749,1.);
#751=CARTESIAN_POINT('',(56.199999,29.749822,100.));
#752=LINE('',#751,#750);
#753=CARTESIAN_POINT('',(56.199999,29.749822,100.));
#754=VERTEX_POINT('',#753);
#755=EDGE_CURVE('E220',#754,#746,#752,.T.);
#756=ORIENTED_EDGE('',*,*,#755,.F.);
#757=DIRECTION('',(-0.00338998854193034,0.999994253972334,0.));
#758=VECTOR('',#757,1.);
#759=CARTESIAN_POINT('',(56.199999,29.749822,100.));
#760=LINE('',#759,#758);
#761=EDGE_CURVE('E210',#723,#754,#760,.T.);
#762=ORIENTED_EDGE('',*,*,#761,.F.);
#763=ORIENTED_EDGE('',*,*,#724,.T.);
#764=EDGE_LOOP('',(#748,#756,#762,#763));
#765=FACE_BOUND('',#764,.T.);
#766=ADVANCED_FACE('F412',(#765),#740,.F.);
#767=CARTESIAN_POINT('',(18.799999,29.749822,100.));
#768=DIRECTION('',(0.,-1.,0.));
#769=DIRECTION('',(0.,0.,-1.));
#770=AXIS2_PLACEMENT_3D('',#767,#768,#769);
#771=PLANE('',#770);
#772=DIRECTION('',(-1.,0.,0.));
#773=VECTOR('',#772,1.);
#774=CARTESIAN_POINT('',(18.799999,29.749822,0.));
#775=LINE('',#774,#773);
#776=CARTESIAN_POINT('',(18.799999,29.749822,0.));
#777=VERTEX_POINT('',#776);
#778=EDGE_CURVE('E218',#746,#777,#775,.T.);
#779=ORIENTED_EDGE('',*,*,#778,.T.);
#780=DIRECTION('',(0.,0.,-1.));
#781=VECTOR('',#780,1.);
#782=CARTESIAN_POINT('',(18.799999,29.749822,100.));
#783=LINE('',#782,#781);
#784=CARTESIAN_POINT('',(18.799999,29.749822,100.));
#785=VERTEX_POINT('',#784);
#786=EDGE_CURVE('E216',#785,#777,#783,.T.);
#787=ORIENTED_EDGE('',*,*,#786,.F.);
#788=DIRECTION('',(-1.,0.,0.));
#789=VECTOR('',#788,1.);
#790=CARTESIAN_POINT('',(56.100019,29.749822,100.));
#791=LINE('',#790,#789);
#792=EDGE_CURVE('E203',#754,#785,#791,.T.);
#793=ORIENTED_EDGE('',*,*,#792,.F.);
#794=ORIENTED_EDGE('',*,*,#755,.T.);
#795=EDGE_LOOP('',(#779,#787,#793,#794));
#796=FACE_BOUND('',#795,.T.);
#797=ADVANCED_FACE('F217',(#796),#771,.F.);
#798=CARTESIAN_POINT('',(18.699981,0.246057,100.));
#799=DIRECTION('',(0.999994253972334,-0.00338998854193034,0.));
#800=DIRECTION('',(0.00338998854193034,0.999994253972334,0.));
#801=AXIS2_PLACEMENT_3D('',#798,#799,#800);
#802=PLANE('',#801);
#803=DIRECTION('',(-0.00338998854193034,-0.999994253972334,0.));
#804=VECTOR('',#803,1.);
#805=CARTESIAN_POINT('',(18.699981,0.246057,0.));
#806=LINE('',#805,#804);
#807=CARTESIAN_POINT('',(18.699981,0.246057,0.));
#808=VERTEX_POINT('',#807);
#809=EDGE_CURVE('E282',#777,#808,#806,.T.);
#810=ORIENTED_EDGE('',*,*,#809,.T.);
#811=DIRECTION('',(0.,0.,-1.));
#812=VECTOR('',#811,1.);
#813=CARTESIAN_POINT('',(18.699981,0.246057,100.));
#814=LINE('',#813,#812);
#815=CARTESIAN_POINT('',(18.699981,0.246057,100.));
#816=VERTEX_POINT('',#815);
#817=EDGE_CURVE('E221',#816,#808,#814,.T.);
#818=ORIENTED_EDGE('',*,*,#817,.F.);
#819=DIRECTION('',(-0.00338998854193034,-0.999994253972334,0.));
#820=VECTOR('',#819,1.);
#821=CARTESIAN_POINT('',(18.699981,0.246057,100.));
#822=LINE('',#821,#820);
#823=EDGE_CURVE('E207',#785,#816,#822,.T.);
#824=ORIENTED_EDGE('',*,*,#823,.F.);
#825=ORIENTED_EDGE('',*,*,#786,.T.);
#826=EDGE_LOOP('',(#810,#818,#824,#825));
#827=FACE_BOUND('',#826,.T.);
#828=ADVANCED_FACE('F223',(#827),#802,.F.);
#829=CARTESIAN_POINT('',(0.,0.246057,100.));
#830=DIRECTION('',(0.,-1.,0.));
#831=DIRECTION('',(0.,0.,-1.));
#832=AXIS2_PLACEMENT_3D('',#829,#830,#831);
#833=PLANE('',#832);
#834=DIRECTION('',(-1.,0.,0.));
#835=VECTOR('',#834,1.);
#836=CARTESIAN_POINT('',(0.,0.246057,0.));
#837=LINE('',#836,#835);
#838=EDGE_CURVE('E130',#808,#29,#837,.T.);
#839=ORIENTED_EDGE('',*,*,#838,.T.);
#840=ORIENTED_EDGE('',*,*,#54,.F.);
#841=DIRECTION('',(-1.,0.,0.));
#842=VECTOR('',#841,1.);
#843=CARTESIAN_POINT('',(18.600001,0.246057,100.));
#844=LINE('',#843,#842);
#845=EDGE_CURVE('E53',#816,#47,#844,.T.);
#846=ORIENTED_EDGE('',*,*,#845,.F.);
#847=ORIENTED_EDGE('',*,*,#817,.T.);
#848=EDGE_LOOP('',(#839,#840,#846,#847));
#849=FACE_BOUND('',#848,.T.);
#850=ADVANCED_FACE('F415',(#849),#833,.F.);
#851=CARTESIAN_POINT('',(0.,0.,100.));
#852=DIRECTION('',(0.,0.,-1.));
#853=DIRECTION('',(-1.,0.,0.));
#854=AXIS2_PLACEMENT_3D('',#851,#852,#853);
#855=PLANE('',#854);
#856=ORIENTED_EDGE('',*,*,#48,.T.);
#857=ORIENTED_EDGE('',*,*,#106,.T.);
#858=ORIENTED_EDGE('',*,*,#137,.T.);
#859=ORIENTED_EDGE('',*,*,#212,.T.);
#860=ORIENTED_EDGE('',*,*,#243,.T.);
#861=ORIENTED_EDGE('',*,*,#296,.T.);
#862=ORIENTED_EDGE('',*,*,#327,.T.);
#863=ORIENTED_EDGE('',*,*,#358,.T.);
#864=ORIENTED_EDGE('',*,*,#389,.T.);
#865=ORIENTED_EDGE('',*,*,#420,.T.);
#866=ORIENTED_EDGE('',*,*,#451,.T.);
#867=ORIENTED_EDGE('',*,*,#482,.T.);
#868=ORIENTED_EDGE('',*,*,#513,.T.);
#869=ORIENTED_EDGE('',*,*,#544,.T.);
#870=ORIENTED_EDGE('',*,*,#575,.T.);
#871=ORIENTED_EDGE('',*,*,#606,.T.);
#872=ORIENTED_EDGE('',*,*,#637,.T.);
#873=ORIENTED_EDGE('',*,*,#668,.T.);
#874=ORIENTED_EDGE('',*,*,#699,.T.);
#875=ORIENTED_EDGE('',*,*,#730,.T.);
#876=ORIENTED_EDGE('',*,*,#761,.T.);
#877=ORIENTED_EDGE('',*,*,#792,.T.);
#878=ORIENTED_EDGE('',*,*,#823,.T.);
#879=ORIENTED_EDGE('',*,*,#845,.T.);
#880=EDGE_LOOP('',(#856,#857,#858,#859,#860,#861,#862,#863,#864,#865,#866,#867,#868,#869,#870,
#871,#872,#873,#874,#875,#876,#877,#878,#879));
#881=FACE_BOUND('',#880,.T.);
#882=ADVANCED_FACE('F205',(#881),#855,.F.);
#883=CARTESIAN_POINT('',(0.,0.,0.));
#884=DIRECTION('',(0.,0.,-1.));
#885=DIRECTION('',(-1.,0.,0.));
#886=AXIS2_PLACEMENT_3D('',#883,#884,#885);
#887=PLANE('',#886);
#888=ORIENTED_EDGE('',*,*,#32,.F.);
#889=ORIENTED_EDGE('',*,*,#838,.F.);
#890=ORIENTED_EDGE('',*,*,#809,.F.);
#891=ORIENTED_EDGE('',*,*,#778,.F.);
#892=ORIENTED_EDGE('',*,*,#747,.F.);
#893=ORIENTED_EDGE('',*,*,#716,.F.);
#894=ORIENTED_EDGE('',*,*,#685,.F.);
#895=ORIENTED_EDGE('',*,*,#654,.F.);
#896=ORIENTED_EDGE('',*,*,#623,.F.);
#897=ORIENTED_EDGE('',*,*,#592,.F.);
#898=ORIENTED_EDGE('',*,*,#561,.F.);
#899=ORIENTED_EDGE('',*,*,#530,.F.);
#900=ORIENTED_EDGE('',*,*,#499,.F.);
#901=ORIENTED_EDGE('',*,*,#468,.F.);
#902=ORIENTED_EDGE('',*,*,#437,.F.);
#903=ORIENTED_EDGE('',*,*,#406,.F.);
#904=ORIENTED_EDGE('',*,*,#375,.F.);
#905=ORIENTED_EDGE('',*,*,#344,.F.);
#906=ORIENTED_EDGE('',*,*,#313,.F.);
#907=ORIENTED_EDGE('',*,*,#282,.F.);
#908=ORIENTED_EDGE('',*,*,#229,.F.);
#909=ORIENTED_EDGE('',*,*,#198,.F.);
#910=ORIENTED_EDGE('',*,*,#123,.F.);
#911=ORIENTED_EDGE('',*,*,#92,.F.);
#912=EDGE_LOOP('',(#888,#889,#890,#891,#892,#893,#894,#895,#896,#897,#898,#899,#900,#901,#902,
#903,#904,#905,#906,#907,#908,#909,#910,#911));
#913=FACE_BOUND('',#912,.T.);
#914=ADVANCED_FACE('F413',(#913),#887,.T.);
#915=CARTESIAN_POINT('',(320.,29.749822,75.));
#916=DIRECTION('',(0.,-1.,0.));
#917=DIRECTION('',(1.,0.,0.));
#918=AXIS2_PLACEMENT_3D('',#915,#916,#917);
#919=CYLINDRICAL_SURFACE('',#918,3.25000000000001);
#920=CARTESIAN_POINT('',(323.25,0.,75.));
#921=CARTESIAN_POINT('',(323.25,-0.10416666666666,75.));
#922=CARTESIAN_POINT('',(323.25,-0.208333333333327,75.));
#923=CARTESIAN_POINT('',(323.25,-0.41666666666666,75.));
#924=CARTESIAN_POINT('',(323.25,-0.520833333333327,75.));
#925=CARTESIAN_POINT('',(323.25,-0.72916666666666,75.));
#926=CARTESIAN_POINT('',(323.25,-0.833333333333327,75.));
#927=CARTESIAN_POINT('',(323.25,-1.04166666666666,75.));
#928=CARTESIAN_POINT('',(323.25,-1.14583333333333,75.));
#929=CARTESIAN_POINT('',(323.25,-1.35416666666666,75.));
#930=CARTESIAN_POINT('',(323.25,-1.45833333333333,75.));
#931=CARTESIAN_POINT('',(323.25,-1.66666666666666,75.));
#932=CARTESIAN_POINT('',(323.25,-1.77083333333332,75.));
#933=CARTESIAN_POINT('',(323.25,-1.97916666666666,75.));
#934=CARTESIAN_POINT('',(323.25,-2.08333333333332,75.));
#935=CARTESIAN_POINT('',(323.25,-2.29166666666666,75.));
#936=CARTESIAN_POINT('',(323.25,-2.39583333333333,75.));
#937=CARTESIAN_POINT('',(323.25,-2.60416666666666,75.));
#938=CARTESIAN_POINT('',(323.25,-2.70833333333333,75.));
#939=CARTESIAN_POINT('',(323.25,-2.91666666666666,75.));
#940=CARTESIAN_POINT('',(323.25,-3.02083333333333,75.));
#941=CARTESIAN_POINT('',(323.25,-3.22916666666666,75.));
#942=CARTESIAN_POINT('',(323.25,-3.33333333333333,75.));
#943=CARTESIAN_POINT('',(323.25,-3.54166666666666,75.));
#944=CARTESIAN_POINT('',(323.25,-3.64583333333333,75.));
#945=CARTESIAN_POINT('',(323.25,-3.85416666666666,75.));
#946=CARTESIAN_POINT('',(323.25,-3.95833333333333,75.));
#947=CARTESIAN_POINT('',(323.25,-4.16666666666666,75.));
#948=CARTESIAN_POINT('',(323.25,-4.27083333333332,75.));
#949=CARTESIAN_POINT('',(323.25,-4.47916666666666,75.));
#950=CARTESIAN_POINT('',(323.25,-4.58333333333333,75.));
#951=CARTESIAN_POINT('',(323.25,-4.79166666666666,75.));
#952=CARTESIAN_POINT('',(323.25,-4.89583333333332,75.));
#953=CARTESIAN_POINT('',(323.25,-5.10416666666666,75.));
#954=CARTESIAN_POINT('',(323.25,-5.20833333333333,75.));
#955=CARTESIAN_POINT('',(323.25,-5.41666666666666,75.));
#956=CARTESIAN_POINT('',(323.25,-5.52083333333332,75.));
#957=CARTESIAN_POINT('',(323.25,-5.72916666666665,75.));
#958=CARTESIAN_POINT('',(323.25,-5.83333333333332,75.));
#959=CARTESIAN_POINT('',(323.25,-6.04166666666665,75.));
#960=CARTESIAN_POINT('',(323.25,-6.14583333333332,75.));
#961=CARTESIAN_POINT('',(323.25,-6.35416666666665,75.));
#962=CARTESIAN_POINT('',(323.25,-6.45833333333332,75.));
#963=CARTESIAN_POINT('',(323.25,-6.66666666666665,75.));
#964=CARTESIAN_POINT('',(323.25,-6.77083333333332,75.));
#965=CARTESIAN_POINT('',(323.25,-6.97916666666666,75.));
#966=CARTESIAN_POINT('',(323.25,-7.08333333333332,75.));
#967=CARTESIAN_POINT('',(323.25,-7.29166666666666,75.));
#968=CARTESIAN_POINT('',(323.25,-7.39583333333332,75.));
#969=CARTESIAN_POINT('',(323.25,-7.60416666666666,75.));
#970=CARTESIAN_POINT('',(323.25,-7.70833333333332,75.));
#971=CARTESIAN_POINT('',(323.25,-7.91666666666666,75.));
#972=CARTESIAN_POINT('',(323.25,-8.02083333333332,75.));
#973=CARTESIAN_POINT('',(323.25,-8.22916666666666,75.));
#974=CARTESIAN_POINT('',(323.25,-8.33333333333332,75.));
#975=CARTESIAN_POINT('',(323.25,-8.54166666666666,75.));
#976=CARTESIAN_POINT('',(323.25,-8.64583333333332,75.));
#977=CARTESIAN_POINT('',(323.25,-8.85416666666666,75.));
#978=CARTESIAN_POINT('',(323.25,-8.95833333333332,75.));
#979=CARTESIAN_POINT('',(323.25,-9.16666666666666,75.));
#980=CARTESIAN_POINT('',(323.25,-9.27083333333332,75.));
#981=CARTESIAN_POINT('',(323.25,-9.47916666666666,75.));
#982=CARTESIAN_POINT('',(323.25,-9.58333333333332,75.));
#983=CARTESIAN_POINT('',(323.25,-9.79166666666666,75.));
#984=CARTESIAN_POINT('',(323.25,-9.89583333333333,75.));
#985=CARTESIAN_POINT('',(323.25,-9.99999999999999,75.));
#986=B_SPLINE_CURVE_WITH_KNOTS('',3,(#920,#921,#922,#923,#924,#925,#926,#927,#928,#929,#930,
#931,#932,#933,#934,#935,#936,#937,#938,#939,#940,#941,#942,#943,#944,#945,#946,#947,#948,#949,
#950,#951,#952,#953,#954,#955,#956,#957,#958,#959,#960,#961,#962,#963,#964,#965,#966,#967,#968,
#969,#970,#971,#972,#973,#974,#975,#976,#977,#978,#979,#980,#981,#982,#983,#984,#985),
.UNSPECIFIED.,.F.,.F.,(4,2,2,2,2,2,2,2,2,2,2,2,2,2,2,2,2,2,2,2,2,2,2,2,2,2,2,2,2,2,2,2,4),(0.,
0.3125,0.625000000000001,0.937500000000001,1.25,1.5625,1.875,2.1875,2.5,2.8125,3.125,3.4375,
3.75,4.0625,4.37499999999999,4.6875,4.99999999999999,5.3125,5.62499999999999,5.93749999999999,
6.25,6.5625,6.875,7.1875,7.5,7.8125,8.125,8.4375,8.75,9.0625,9.375,9.6875,10.),.UNSPECIFIED.);
#987=EDGE_CURVE('BSEAM617',#271,#176,#986,.T.);
#988=ORIENTED_EDGE('',*,*,#272,.F.);
#989=ORIENTED_EDGE('',*,*,#177,.F.);
#990=ORIENTED_EDGE('',*,*,#987,.T.);
#991=ORIENTED_EDGE('',*,*,#987,.F.);
#992=EDGE_LOOP('',(#988,#990,#989,#991));
#993=FACE_BOUND('',#992,.T.);
#994=ADVANCED_FACE('F617',(#993),#919,.F.);
#995=CARTESIAN_POINT('',(320.,29.749822,25.));
#996=DIRECTION('',(0.,-1.,0.));
#997=DIRECTION('',(1.,0.,0.));
#998=AXIS2_PLACEMENT_3D('',#995,#996,#997);
#999=CYLINDRICAL_SURFACE('',#998,3.25000000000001);
#1000=CARTESIAN_POINT('',(323.25,0.,25.));
#1001=CARTESIAN_POINT('',(323.25,-0.10416666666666,25.));
#1002=CARTESIAN_POINT('',(323.25,-0.208333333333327,25.));
#1003=CARTESIAN_POINT('',(323.25,-0.41666666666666,25.));
#1004=CARTESIAN_POINT('',(323.25,-0.520833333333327,25.));
#1005=CARTESIAN_POINT('',(323.25,-0.72916666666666,25.));
#1006=CARTESIAN_POINT('',(323.25,-0.833333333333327,25.));
#1007=CARTESIAN_POINT('',(323.25,-1.04166666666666,25.));
#1008=CARTESIAN_POINT('',(323.25,-1.14583333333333,25.));
#1009=CARTESIAN_POINT('',(323.25,-1.35416666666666,25.));
#1010=CARTESIAN_POINT('',(323.25,-1.45833333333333,25.));
#1011=CARTESIAN_POINT('',(323.25,-1.66666666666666,25.));
#1012=CARTESIAN_POINT('',(323.25,-1.77083333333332,25.));
#1013=CARTESIAN_POINT('',(323.25,-1.97916666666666,25.));
#1014=CARTESIAN_POINT('',(323.25,-2.08333333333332,25.));
#1015=CARTESIAN_POINT('',(323.25,-2.29166666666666,25.));
#1016=CARTESIAN_POINT('',(323.25,-2.39583333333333,25.));
#1017=CARTESIAN_POINT('',(323.25,-2.60416666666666,25.));
#1018=CARTESIAN_POINT('',(323.25,-2.70833333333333,25.));
#1019=CARTESIAN_POINT('',(323.25,-2.91666666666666,25.));
#1020=CARTESIAN_POINT('',(323.25,-3.02083333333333,25.));
#1021=CARTESIAN_POINT('',(323.25,-3.22916666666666,25.));
#1022=CARTESIAN_POINT('',(323.25,-3.33333333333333,25.));
#1023=CARTESIAN_POINT('',(323.25,-3.54166666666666,25.));
#1024=CARTESIAN_POINT('',(323.25,-3.64583333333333,25.));
#1025=CARTESIAN_POINT('',(323.25,-3.85416666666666,25.));
#1026=CARTESIAN_POINT('',(323.25,-3.95833333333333,25.));
#1027=CARTESIAN_POINT('',(323.25,-4.16666666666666,25.));
#1028=CARTESIAN_POINT('',(323.25,-4.27083333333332,25.));
#1029=CARTESIAN_POINT('',(323.25,-4.47916666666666,25.));
#1030=CARTESIAN_POINT('',(323.25,-4.58333333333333,25.));
#1031=CARTESIAN_POINT('',(323.25,-4.79166666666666,25.));
#1032=CARTESIAN_POINT('',(323.25,-4.89583333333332,25.));
#1033=CARTESIAN_POINT('',(323.25,-5.10416666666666,25.));
#1034=CARTESIAN_POINT('',(323.25,-5.20833333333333,25.));
#1035=CARTESIAN_POINT('',(323.25,-5.41666666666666,25.));
#1036=CARTESIAN_POINT('',(323.25,-5.52083333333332,25.));
#1037=CARTESIAN_POINT('',(323.25,-5.72916666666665,25.));
#1038=CARTESIAN_POINT('',(323.25,-5.83333333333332,25.));
#1039=CARTESIAN_POINT('',(323.25,-6.04166666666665,25.));
#1040=CARTESIAN_POINT('',(323.25,-6.14583333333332,25.));
#1041=CARTESIAN_POINT('',(323.25,-6.35416666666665,25.));
#1042=CARTESIAN_POINT('',(323.25,-6.45833333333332,25.));
#1043=CARTESIAN_POINT('',(323.25,-6.66666666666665,25.));
#1044=CARTESIAN_POINT('',(323.25,-6.77083333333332,25.));
#1045=CARTESIAN_POINT('',(323.25,-6.97916666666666,25.));
#1046=CARTESIAN_POINT('',(323.25,-7.08333333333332,25.));
#1047=CARTESIAN_POINT('',(323.25,-7.29166666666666,25.));
#1048=CARTESIAN_POINT('',(323.25,-7.39583333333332,25.));
#1049=CARTESIAN_POINT('',(323.25,-7.60416666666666,25.));
#1050=CARTESIAN_POINT('',(323.25,-7.70833333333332,25.));
#1051=CARTESIAN_POINT('',(323.25,-7.91666666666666,25.));
#1052=CARTESIAN_POINT('',(323.25,-8.02083333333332,25.));
#1053=CARTESIAN_POINT('',(323.25,-8.22916666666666,25.));
#1054=CARTESIAN_POINT('',(323.25,-8.33333333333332,25.));
#1055=CARTESIAN_POINT('',(323.25,-8.54166666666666,25.));
#1056=CARTESIAN_POINT('',(323.25,-8.64583333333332,25.));
#1057=CARTESIAN_POINT('',(323.25,-8.85416666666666,25.));
#1058=CARTESIAN_POINT('',(323.25,-8.95833333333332,25.));
#1059=CARTESIAN_POINT('',(323.25,-9.16666666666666,25.));
#1060=CARTESIAN_POINT('',(323.25,-9.27083333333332,25.));
#1061=CARTESIAN_POINT('',(323.25,-9.47916666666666,25.));
#1062=CARTESIAN_POINT('',(323.25,-9.58333333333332,25.));
#1063=CARTESIAN_POINT('',(323.25,-9.79166666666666,25.));
#1064=CARTESIAN_POINT('',(323.25,-9.89583333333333,25.));
#1065=CARTESIAN_POINT('',(323.25,-9.99999999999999,25.));
#1066=B_SPLINE_CURVE_WITH_KNOTS('',3,(#1000,#1001,#1002,#1003,#1004,#1005,#1006,#1007,#1008,
#1009,#1010,#1011,#1012,#1013,#1014,#1015,#1016,#1017,#1018,#1019,#1020,#1021,#1022,#1023,#1024,
#1025,#1026,#1027,#1028,#1029,#1030,#1031,#1032,#1033,#1034,#1035,#1036,#1037,#1038,#1039,#1040,
#1041,#1042,#1043,#1044,#1045,#1046,#1047,#1048,#1049,#1050,#1051,#1052,#1053,#1054,#1055,#1056,
#1057,#1058,#1059,#1060,#1061,#1062,#1063,#1064,#1065),.UNSPECIFIED.,.F.,.F.,(4,2,2,2,2,2,2,2,2,
2,2,2,2,2,2,2,2,2,2,2,2,2,2,2,2,2,2,2,2,2,2,2,4),(0.,0.3125,0.625000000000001,0.937500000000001,
1.25,1.5625,1.875,2.1875,2.5,2.8125,3.125,3.4375,3.75,4.0625,4.37499999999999,4.6875,
4.99999999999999,5.3125,5.62499999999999,5.93749999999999,6.25,6.5625,6.875,7.1875,7.5,7.8125,
8.125,8.4375,8.75,9.0625,9.375,9.6875,10.),.UNSPECIFIED.);
#1067=EDGE_CURVE('BSEAM647',#260,#165,#1066,.T.);
#1068=ORIENTED_EDGE('',*,*,#261,.F.);
#1069=ORIENTED_EDGE('',*,*,#166,.F.);
#1070=ORIENTED_EDGE('',*,*,#1067,.T.);
#1071=ORIENTED_EDGE('',*,*,#1067,.F.);
#1072=EDGE_LOOP('',(#1068,#1070,#1069,#1071));
#1073=FACE_BOUND('',#1072,.T.);
#1074=ADVANCED_FACE('F647',(#1073),#999,.F.);
#1075=CARTESIAN_POINT('',(-10.,29.749822,75.));
#1076=DIRECTION('',(0.,-1.,0.));
#1077=DIRECTION('',(1.,0.,0.));
#1078=AXIS2_PLACEMENT_3D('',#1075,#1076,#1077);
#1079=CYLINDRICAL_SURFACE('',#1078,3.25);
#1080=CARTESIAN_POINT('',(-6.75,-9.99999999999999,75.));
#1081=CARTESIAN_POINT('',(-6.75,-9.89583333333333,75.));
#1082=CARTESIAN_POINT('',(-6.75,-9.79166666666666,75.));
#1083=CARTESIAN_POINT('',(-6.75,-9.58333333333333,75.));
#1084=CARTESIAN_POINT('',(-6.75,-9.47916666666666,75.));
#1085=CARTESIAN_POINT('',(-6.75,-9.27083333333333,75.));
#1086=CARTESIAN_POINT('',(-6.75,-9.16666666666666,75.));
#1087=CARTESIAN_POINT('',(-6.75,-8.95833333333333,75.));
#1088=CARTESIAN_POINT('',(-6.75,-8.85416666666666,75.));
#1089=CARTESIAN_POINT('',(-6.75,-8.64583333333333,75.));
#1090=CARTESIAN_POINT('',(-6.75,-8.54166666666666,75.));
#1091=CARTESIAN_POINT('',(-6.75,-8.33333333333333,75.));
#1092=CARTESIAN_POINT('',(-6.75,-8.22916666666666,75.));
#1093=CARTESIAN_POINT('',(-6.75,-8.02083333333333,75.));
#1094=CARTESIAN_POINT('',(-6.75,-7.91666666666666,75.));
#1095=CARTESIAN_POINT('',(-6.75,-7.70833333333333,75.));
#1096=CARTESIAN_POINT('',(-6.75,-7.60416666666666,75.));
#1097=CARTESIAN_POINT('',(-6.75,-7.39583333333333,75.));
#1098=CARTESIAN_POINT('',(-6.75,-7.29166666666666,75.));
#1099=CARTESIAN_POINT('',(-6.75,-7.08333333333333,75.));
#1100=CARTESIAN_POINT('',(-6.75,-6.97916666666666,75.));
#1101=CARTESIAN_POINT('',(-6.75,-6.77083333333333,75.));
#1102=CARTESIAN_POINT('',(-6.75,-6.66666666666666,75.));
#1103=CARTESIAN_POINT('',(-6.75,-6.45833333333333,75.));
#1104=CARTESIAN_POINT('',(-6.75,-6.35416666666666,75.));
#1105=CARTESIAN_POINT('',(-6.75,-6.14583333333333,75.));
#1106=CARTESIAN_POINT('',(-6.75,-6.04166666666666,75.));
#1107=CARTESIAN_POINT('',(-6.75,-5.83333333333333,75.));
#1108=CARTESIAN_POINT('',(-6.75,-5.72916666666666,75.));
#1109=CARTESIAN_POINT('',(-6.75,-5.52083333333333,75.));
#1110=CARTESIAN_POINT('',(-6.75,-5.41666666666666,75.));
#1111=CARTESIAN_POINT('',(-6.75,-5.20833333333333,75.));
#1112=CARTESIAN_POINT('',(-6.75,-5.10416666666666,75.));
#1113=CARTESIAN_POINT('',(-6.75,-4.89583333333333,75.));
#1114=CARTESIAN_POINT('',(-6.75,-4.79166666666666,75.));
#1115=CARTESIAN_POINT('',(-6.75,-4.58333333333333,75.));
#1116=CARTESIAN_POINT('',(-6.75,-4.47916666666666,75.));
#1117=CARTESIAN_POINT('',(-6.75,-4.27083333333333,75.));
#1118=CARTESIAN_POINT('',(-6.75,-4.16666666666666,75.));
#1119=CARTESIAN_POINT('',(-6.75,-3.95833333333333,75.));
#1120=CARTESIAN_POINT('',(-6.75,-3.85416666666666,75.));
#1121=CARTESIAN_POINT('',(-6.75,-3.64583333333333,75.));
#1122=CARTESIAN_POINT('',(-6.75,-3.54166666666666,75.));
#1123=CARTESIAN_POINT('',(-6.75,-3.33333333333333,75.));
#1124=CARTESIAN_POINT('',(-6.75,-3.22916666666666,75.));
#1125=CARTESIAN_POINT('',(-6.75,-3.02083333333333,75.));
#1126=CARTESIAN_POINT('',(-6.75,-2.91666666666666,75.));
#1127=CARTESIAN_POINT('',(-6.75,-2.70833333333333,75.));
#1128=CARTESIAN_POINT('',(-6.75,-2.60416666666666,75.));
#1129=CARTESIAN_POINT('',(-6.75,-2.39583333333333,75.));
#1130=CARTESIAN_POINT('',(-6.75,-2.29166666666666,75.));
#1131=CARTESIAN_POINT('',(-6.75,-2.08333333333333,75.));
#1132=CARTESIAN_POINT('',(-6.75,-1.97916666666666,75.));
#1133=CARTESIAN_POINT('',(-6.75,-1.77083333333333,75.));
#1134=CARTESIAN_POINT('',(-6.75,-1.66666666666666,75.));
#1135=CARTESIAN_POINT('',(-6.75,-1.45833333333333,75.));
#1136=CARTESIAN_POINT('',(-6.75,-1.35416666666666,75.));
#1137=CARTESIAN_POINT('',(-6.75,-1.14583333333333,75.));
#1138=CARTESIAN_POINT('',(-6.75,-1.04166666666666,75.));
#1139=CARTESIAN_POINT('',(-6.75,-0.833333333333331,75.));
#1140=CARTESIAN_POINT('',(-6.75,-0.729166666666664,75.));
#1141=CARTESIAN_POINT('',(-6.75,-0.52083333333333,75.));
#1142=CARTESIAN_POINT('',(-6.75,-0.416666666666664,75.));
#1143=CARTESIAN_POINT('',(-6.75,-0.20833333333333,75.));
#1144=CARTESIAN_POINT('',(-6.75,-0.104166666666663,75.));
#1145=CARTESIAN_POINT('',(-6.75,0.,75.));
#1146=B_SPLINE_CURVE_WITH_KNOTS('',3,(#1080,#1081,#1082,#1083,#1084,#1085,#1086,#1087,#1088,
#1089,#1090,#1091,#1092,#1093,#1094,#1095,#1096,#1097,#1098,#1099,#1100,#1101,#1102,#1103,#1104,
#1105,#1106,#1107,#1108,#1109,#1110,#1111,#1112,#1113,#1114,#1115,#1116,#1117,#1118,#1119,#1120,
#1121,#1122,#1123,#1124,#1125,#1126,#1127,#1128,#1129,#1130,#1131,#1132,#1133,#1134,#1135,#1136,
#1137,#1138,#1139,#1140,#1141,#1142,#1143,#1144,#1145),.UNSPECIFIED.,.F.,.F.,(4,2,2,2,2,2,2,2,2,
2,2,2,2,2,2,2,2,2,2,2,2,2,2,2,2,2,2,2,2,2,2,2,4),(0.,0.3125,0.625000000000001,0.937500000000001,
1.25,1.5625,1.875,2.1875,2.5,2.8125,3.125,3.4375,3.75,4.0625,4.375,4.6875,5.,5.3125,
5.62500000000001,5.9375,6.25,6.5625,6.875,7.1875,7.5,7.8125,8.125,8.4375,8.75,9.0625,9.375,
9.6875,10.),.UNSPECIFIED.);
#1147=EDGE_CURVE('BSEAM657',#187,#81,#1146,.T.);
#1148=ORIENTED_EDGE('',*,*,#188,.F.);
#1149=ORIENTED_EDGE('',*,*,#82,.F.);
#1150=ORIENTED_EDGE('',*,*,#1147,.T.);
#1151=ORIENTED_EDGE('',*,*,#1147,.F.);
#1152=EDGE_LOOP('',(#1148,#1150,#1149,#1151));
#1153=FACE_BOUND('',#1152,.T.);
#1154=ADVANCED_FACE('F657',(#1153),#1079,.F.);
#1155=CARTESIAN_POINT('',(-10.,29.749822,25.));
#1156=DIRECTION('',(0.,-1.,0.));
#1157=DIRECTION('',(1.,0.,0.));
#1158=AXIS2_PLACEMENT_3D('',#1155,#1156,#1157);
#1159=CYLINDRICAL_SURFACE('',#1158,3.25);
#1160=CARTESIAN_POINT('',(-6.75,-9.99999999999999,25.));
#1161=CARTESIAN_POINT('',(-6.75,-9.89583333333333,25.));
#1162=CARTESIAN_POINT('',(-6.75,-9.79166666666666,25.));
#1163=CARTESIAN_POINT('',(-6.75,-9.58333333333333,25.));
#1164=CARTESIAN_POINT('',(-6.75,-9.47916666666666,25.));
#1165=CARTESIAN_POINT('',(-6.75,-9.27083333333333,25.));
#1166=CARTESIAN_POINT('',(-6.75,-9.16666666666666,25.));
#1167=CARTESIAN_POINT('',(-6.75,-8.95833333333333,25.));
#1168=CARTESIAN_POINT('',(-6.75,-8.85416666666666,25.));
#1169=CARTESIAN_POINT('',(-6.75,-8.64583333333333,25.));
#1170=CARTESIAN_POINT('',(-6.75,-8.54166666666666,25.));
#1171=CARTESIAN_POINT('',(-6.75,-8.33333333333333,25.));
#1172=CARTESIAN_POINT('',(-6.75,-8.22916666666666,25.));
#1173=CARTESIAN_POINT('',(-6.75,-8.02083333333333,25.));
#1174=CARTESIAN_POINT('',(-6.75,-7.91666666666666,25.));
#1175=CARTESIAN_POINT('',(-6.75,-7.70833333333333,25.));
#1176=CARTESIAN_POINT('',(-6.75,-7.60416666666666,25.));
#1177=CARTESIAN_POINT('',(-6.75,-7.39583333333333,25.));
#1178=CARTESIAN_POINT('',(-6.75,-7.29166666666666,25.));
#1179=CARTESIAN_POINT('',(-6.75,-7.08333333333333,25.));
#1180=CARTESIAN_POINT('',(-6.75,-6.97916666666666,25.));
#1181=CARTESIAN_POINT('',(-6.75,-6.77083333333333,25.));
#1182=CARTESIAN_POINT('',(-6.75,-6.66666666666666,25.));
#1183=CARTESIAN_POINT('',(-6.75,-6.45833333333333,25.));
#1184=CARTESIAN_POINT('',(-6.75,-6.35416666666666,25.));
#1185=CARTESIAN_POINT('',(-6.75,-6.14583333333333,25.));
#1186=CARTESIAN_POINT('',(-6.75,-6.04166666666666,25.));
#1187=CARTESIAN_POINT('',(-6.75,-5.83333333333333,25.));
#1188=CARTESIAN_POINT('',(-6.75,-5.72916666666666,25.));
#1189=CARTESIAN_POINT('',(-6.75,-5.52083333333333,25.));
#1190=CARTESIAN_POINT('',(-6.75,-5.41666666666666,25.));
#1191=CARTESIAN_POINT('',(-6.75,-5.20833333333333,25.));
#1192=CARTESIAN_POINT('',(-6.75,-5.10416666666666,25.));
#1193=CARTESIAN_POINT('',(-6.75,-4.89583333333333,25.));
#1194=CARTESIAN_POINT('',(-6.75,-4.79166666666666,25.));
#1195=CARTESIAN_POINT('',(-6.75,-4.58333333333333,25.));
#1196=CARTESIAN_POINT('',(-6.75,-4.47916666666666,25.));
#1197=CARTESIAN_POINT('',(-6.75,-4.27083333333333,25.));
#1198=CARTESIAN_POINT('',(-6.75,-4.16666666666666,25.));
#1199=CARTESIAN_POINT('',(-6.75,-3.95833333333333,25.));
#1200=CARTESIAN_POINT('',(-6.75,-3.85416666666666,25.));
#1201=CARTESIAN_POINT('',(-6.75,-3.64583333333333,25.));
#1202=CARTESIAN_POINT('',(-6.75,-3.54166666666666,25.));
#1203=CARTESIAN_POINT('',(-6.75,-3.33333333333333,25.));
#1204=CARTESIAN_POINT('',(-6.75,-3.22916666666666,25.));
#1205=CARTESIAN_POINT('',(-6.75,-3.02083333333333,25.));
#1206=CARTESIAN_POINT('',(-6.75,-2.91666666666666,25.));
#1207=CARTESIAN_POINT('',(-6.75,-2.70833333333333,25.));
#1208=CARTESIAN_POINT('',(-6.75,-2.60416666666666,25.));
#1209=CARTESIAN_POINT('',(-6.75,-2.39583333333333,25.));
#1210=CARTESIAN_POINT('',(-6.75,-2.29166666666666,25.));
#1211=CARTESIAN_POINT('',(-6.75,-2.08333333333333,25.));
#1212=CARTESIAN_POINT('',(-6.75,-1.97916666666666,25.));
#1213=CARTESIAN_POINT('',(-6.75,-1.77083333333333,25.));
#1214=CARTESIAN_POINT('',(-6.75,-1.66666666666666,25.));
#1215=CARTESIAN_POINT('',(-6.75,-1.45833333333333,25.));
#1216=CARTESIAN_POINT('',(-6.75,-1.35416666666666,25.));
#1217=CARTESIAN_POINT('',(-6.75,-1.14583333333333,25.));
#1218=CARTESIAN_POINT('',(-6.75,-1.04166666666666,25.));
#1219=CARTESIAN_POINT('',(-6.75,-0.833333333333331,25.));
#1220=CARTESIAN_POINT('',(-6.75,-0.729166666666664,25.));
#1221=CARTESIAN_POINT('',(-6.75,-0.52083333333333,25.));
#1222=CARTESIAN_POINT('',(-6.75,-0.416666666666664,25.));
#1223=CARTESIAN_POINT('',(-6.75,-0.20833333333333,25.));
#1224=CARTESIAN_POINT('',(-6.75,-0.104166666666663,25.));
#1225=CARTESIAN_POINT('',(-6.75,0.,25.));
#1226=B_SPLINE_CURVE_WITH_KNOTS('',3,(#1160,#1161,#1162,#1163,#1164,#1165,#1166,#1167,#1168,
#1169,#1170,#1171,#1172,#1173,#1174,#1175,#1176,#1177,#1178,#1179,#1180,#1181,#1182,#1183,#1184,
#1185,#1186,#1187,#1188,#1189,#1190,#1191,#1192,#1193,#1194,#1195,#1196,#1197,#1198,#1199,#1200,
#1201,#1202,#1203,#1204,#1205,#1206,#1207,#1208,#1209,#1210,#1211,#1212,#1213,#1214,#1215,#1216,
#1217,#1218,#1219,#1220,#1221,#1222,#1223,#1224,#1225),.UNSPECIFIED.,.F.,.F.,(4,2,2,2,2,2,2,2,2,
2,2,2,2,2,2,2,2,2,2,2,2,2,2,2,2,2,2,2,2,2,2,2,4),(0.,0.3125,0.625000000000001,0.937500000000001,
1.25,1.5625,1.875,2.1875,2.5,2.8125,3.125,3.4375,3.75,4.0625,4.375,4.6875,5.,5.3125,
5.62500000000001,5.9375,6.25,6.5625,6.875,7.1875,7.5,7.8125,8.125,8.4375,8.75,9.0625,9.375,
9.6875,10.),.UNSPECIFIED.);
#1227=EDGE_CURVE('BSEAM667',#154,#70,#1226,.T.);
#1228=ORIENTED_EDGE('',*,*,#155,.F.);
#1229=ORIENTED_EDGE('',*,*,#71,.F.);
#1230=ORIENTED_EDGE('',*,*,#1227,.T.);
#1231=ORIENTED_EDGE('',*,*,#1227,.F.);
#1232=EDGE_LOOP('',(#1228,#1230,#1229,#1231));
#1233=FACE_BOUND('',#1232,.T.);
#1234=ADVANCED_FACE('F667',(#1233),#1159,.F.);
#1235=CLOSED_SHELL('',(#58,#111,#142,#217,#248,#301,#332,#363,#394,#425,#456,#487,#518,#549,
#580,#611,#642,#673,#704,#735,#766,#797,#828,#850,#882,#914,#994,#1074,#1154,#1234));
#1236=MANIFOLD_SOLID_BREP('B2',#1235);
#1237=ADVANCED_BREP_SHAPE_REPRESENTATION('',(#18,#1236),#14);
#1238=SHAPE_DEFINITION_REPRESENTATION(#9,#1237);
ENDSEC;
END-ISO-10303-21;
